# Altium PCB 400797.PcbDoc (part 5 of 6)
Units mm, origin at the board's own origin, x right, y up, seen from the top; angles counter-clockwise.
Board outline 155 x 63.5 mm, 4 copper layers (Top Layer, Mid-Layer 1, Mid-Layer 2, Bottom Layer), stack 1.514 mm thick; 333 components, 292 nets, 1555 pads, 2205 vias.

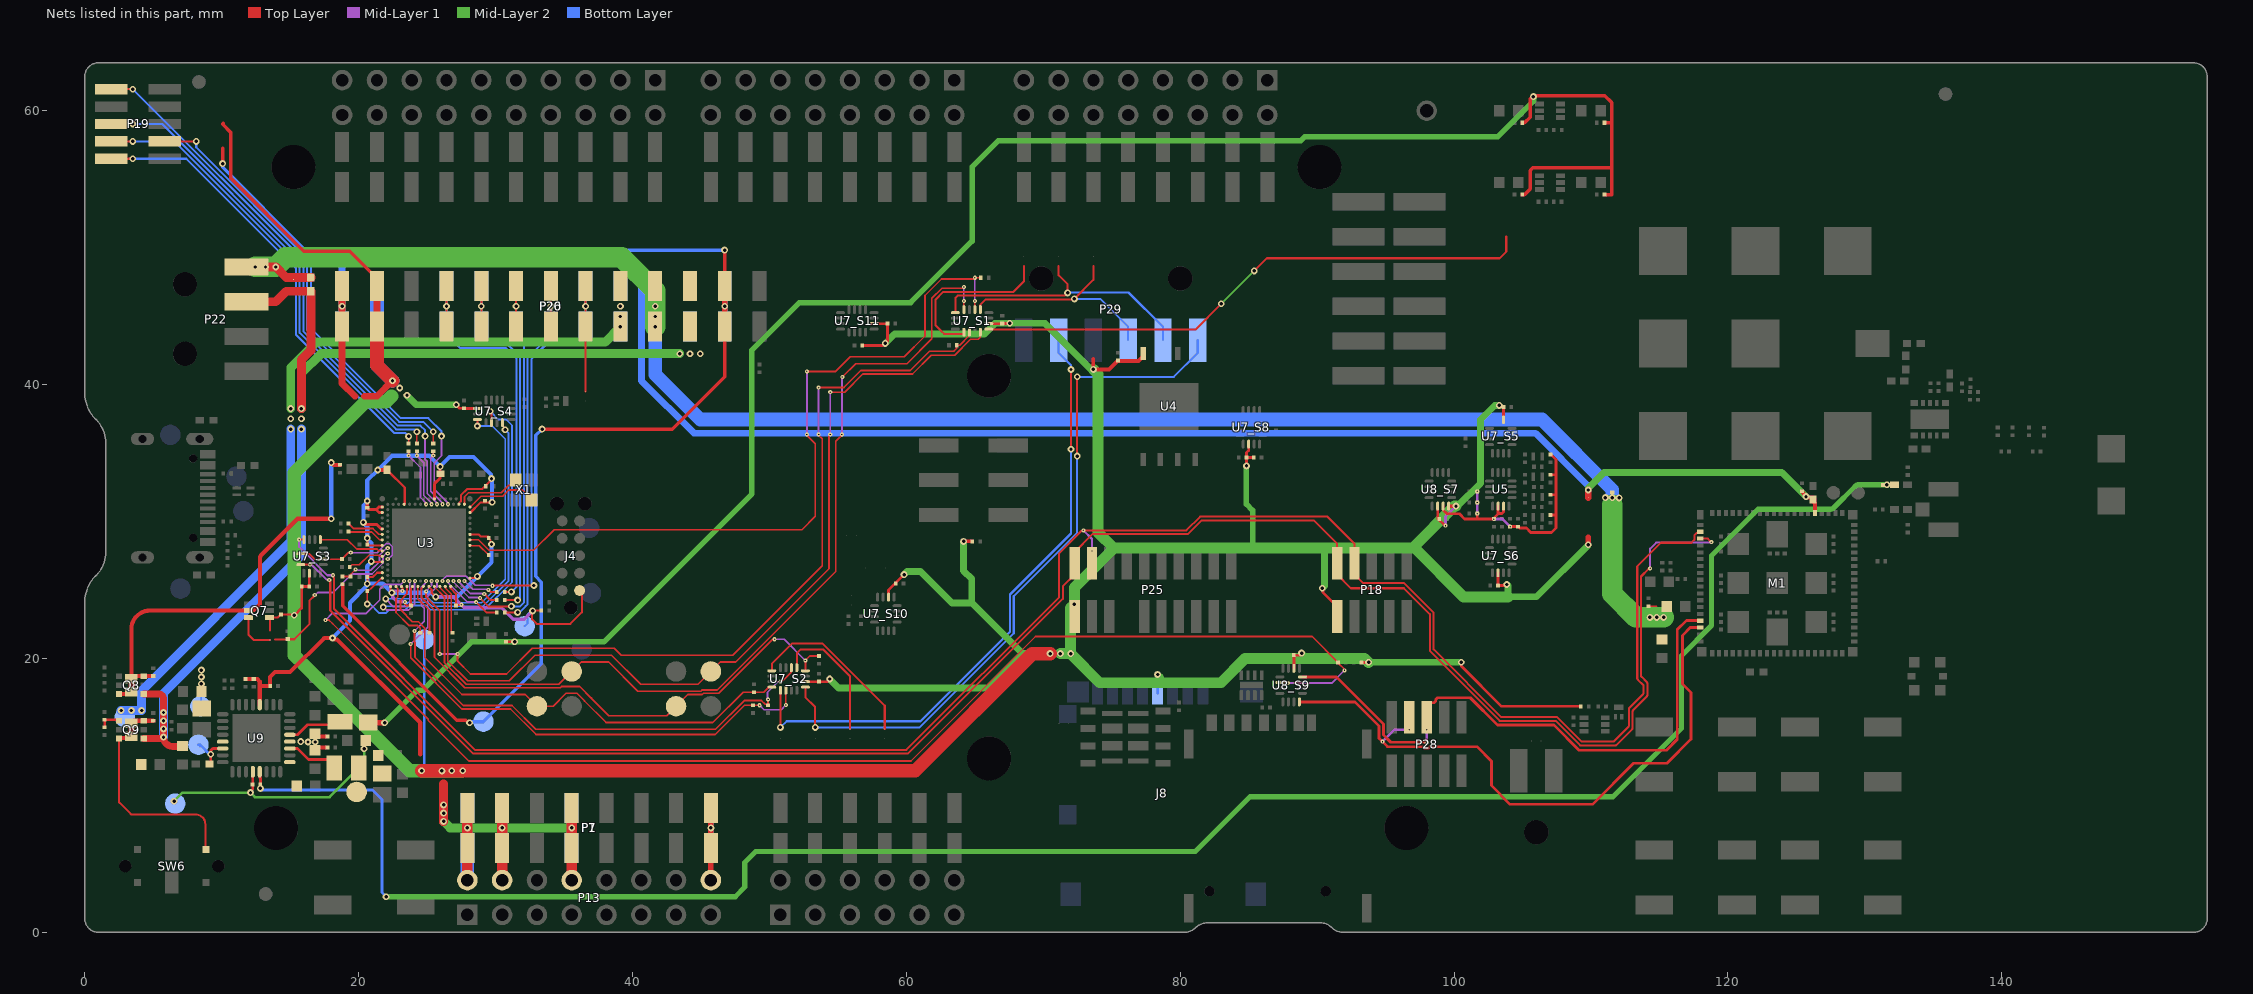
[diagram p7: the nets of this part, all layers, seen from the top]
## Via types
v1: diameter 0.5, hole 0.25, Top Layer to Bottom Layer, tented both sides, 1614 vias
v2: diameter 0.3, hole 0.1, Top Layer to Mid-Layer 1, tented top, 485 vias
v3: diameter 0.3, hole 0.1, Top Layer to Mid-Layer 1, tented both sides, 97 vias
v4: diameter 0.61, hole 0.305, Top Layer to Bottom Layer, tented both sides, 9 vias

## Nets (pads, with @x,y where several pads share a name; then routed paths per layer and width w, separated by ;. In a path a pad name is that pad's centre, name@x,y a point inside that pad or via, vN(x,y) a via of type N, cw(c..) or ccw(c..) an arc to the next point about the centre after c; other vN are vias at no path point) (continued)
SIM_IO: M1.17 P28.4 U8_S9.8 | length 47
  Top Layer w0.203: U8_S9.8@88.7,16.825 92.764,16.825 94.525,15.064 94.525,14.175 v2(94.775,13.925) 95.145,13.555 97.738,13.555 97.844,13.448 98.156,13.448 98.262,13.555 101.659,13.555 102.722,12.492 102.722,10.714 104.089,9.347 110.102,9.347 113.104,12.348 115.543,12.348 117.3,14.106 117.3,17.5 116.672,18.128 116.672,21.672 117.25,22.25 M1.17@117.975,22.25
  Mid-Layer 1 w0.203: v2(94.775,13.925) 95.65,14.8 v2(96.73,14.8)
SIM_RST: M1.16 P28.6 U8_S9.12 | length 43.8
  Top Layer w0.203: U8_S9.12@88.925,18.65 91.403,18.65 94.853,15.2 94.853,14.406 95.377,13.883 97.874,13.883 97.883,13.873 97.925,13.873 97.974,13.825 v2(98,13.825) ; P28.6@98,15.7 98,16.482 98.278,16.76 98.544,16.76 98.663,16.879 98.663,16.994 98.796,17.127 101.18,17.127 103.168,15.138 107.285,15.138 109.125,13.298 115.498,13.298 116.3,14.1 116.3,22.1 116.974,22.774 117.952,22.774 M1.16@117.975,22.75
  Mid-Layer 1 w0.203: v2(98,13.825) v2(98,14.8)
SIM_SELECT: R63.1 U3.AK8 U8_S9.2 | length 96.1
  Top Layer w0.125: v2(17.575,22.8) 17.836,22.8 18.086,22.55 25.088,15.549 25.088,15.466 28.041,12.513 60.337,12.513 69.426,21.602 89.628,21.602 91.552,19.678 91.552,19.648 91.967,19.233 91.967,19.158 v2(92,19.125) ; U8_S9.2@87.275,18.25 87.8,18.25 v2(87.85,18.2)
  Mid-Layer 1 w0.125: v2(17.575,22.8) 18.063,23.288 20.557,23.288 21.537,24.269 21.537,25.046 21.892,25.4 23.066,25.4 v2(23.325,25.659) ; v2(87.85,18.2) 91.075,18.2 v2(92,19.125)
SW1: L7.2 U9.3 | length 3.9
  Top Layer w0.2: U9.3@14.975,13.425 15.538,13.425 16.341,12.622 17.762,12.622 18.227,12.157 L7.2@18.227,11.997
SW2: L8.2 U9.5 | length 4
  Top Layer w0.2: U9.5@14.975,14.425 15.538,14.425 16.28,15.167 18.402,15.167 L8.2@18.625,15.39
SWD0.RESET: P19.10 R30.2 | length 37.6
  Top Layer w0.125: R30.2@25.45,35.694 v1(25.45,36.55)
  Top Layer w0.15: P19.10@1.936,61.571 v1(3.505,61.571)
  Bottom Layer w0.15: v1(3.505,61.571) 16.235,48.84 16.235,44.001 22.961,37.275 24.725,37.275 v1(25.45,36.55)
SWD0.SWDCLK: P19.4 R29.2 | length 34.8
  Top Layer w0.125: R29.2@24.25,35.694 v1(24.25,36.55)
  Top Layer w0.15: P19.4@1.936,57.761 v1(3.505,57.761)
  Bottom Layer w0.15: v1(3.505,57.761) 6.537,57.761 15.685,48.613 15.685,43.773 22.733,36.725 24.075,36.725 v1(24.25,36.55)
SWD0.SWDIO: P19.2 R28.2 | length 33.5
  Top Layer w0.125: R28.2@23.65,35.694 v1(23.65,36.219)
  Top Layer w0.15: P19.2@1.936,56.491 v1(3.505,56.491)
  Bottom Layer w0.15: v1(3.505,56.491) 7.418,56.491 15.41,48.499 15.41,43.659 22.619,36.45 23.419,36.45 v1(23.65,36.219)
SWD0_CLK: R29.1 U3.B18 | length 4.3
  Top Layer w0.125: v2(24.25,34.809) R29.1@24.25,35.124
  Mid-Layer 1 w0.125: v2(24.25,34.809) 24.762,34.297 24.762,31.897 25.063,31.597 25.065,31.597 25.262,31.399 25.262,31.397 25.325,31.334 v2(25.325,31.259)
SWD0_IO: R28.1 U3.B16 | length 4.4
  Top Layer w0.125: v2(23.65,34.809) R28.1@23.65,35.124
  Mid-Layer 1 w0.125: v2(23.65,34.809) 24.512,33.947 24.512,31.749 24.862,31.399 24.862,31.322 v2(24.925,31.259)
SWD0_RESET: R30.1 U3.B22 | length 4.3
  Top Layer w0.125: v2(25.45,34.809) R30.1@25.45,35.124
  Mid-Layer 1 w0.125: v2(25.45,34.809) 25.262,34.622 25.262,32.199 26.063,31.399 26.063,31.347 26.125,31.284 v2(26.125,31.259)
SWD0_SEL: P19.3 U3.B24 | length 38
  Top Layer w0.15: P19.3@5.836,57.761 v1(8.139,57.761)
  Mid-Layer 1 w0.125: v1(26.05,36.234) 26.05,34.809 25.512,34.272 25.512,32.349 26.462,31.399 26.462,31.322 v2(26.525,31.259)
  Bottom Layer w0.15: v1(8.139,57.761) 8.139,57.325 16.51,48.954 16.51,44.115 23.075,37.55 25.086,37.55 26.05,36.586 v1(26.05,36.234)
SWD0_SWO: P19.6 U3.B20 | length 40.8
  Top Layer w0.15: P19.6@1.936,59.031 v1(3.505,59.031)
  Mid-Layer 1 w0.125: v1(24.85,36.234) 24.85,34.563 25.012,34.4 25.012,32.049 25.662,31.399 25.662,31.347 25.725,31.284 v2(25.725,31.259)
  Bottom Layer w0.15: v1(3.505,59.031) 5.656,59.031 15.96,48.726 15.96,43.887 22.847,37 24.5,37 24.85,36.65 v1(24.85,36.234)
SWD1.RESET: P20.7 P26.7 R27.2 | length 28.8
  Top Layer w0.15: R27.2@30.66,23.359 v1(31.609,23.359) ; P20.7@34.036,44.256 v1(34.036,45.721) P20.7@34.036,47.186
  Bottom Layer w0.15: v1(31.609,23.359) 31.759,23.359 32.2,23.8 32.2,23.825 32.338,23.962 32.338,41.972 34.036,43.671 P26.7@34.036,44.256 v1(34.036,45.721) P26.7@34.036,47.186
SWD1.SWDCLK: P20.5 P26.5 R26.2 | length 29.3
  Top Layer w0.15: P20.5@28.956,43.689 P20.5@28.956,44.256 P20.5@28.956,47.186 ; R26.2@30.66,24.259 v1(31.609,24.259)
  Bottom Layer w0.15: P26.5@28.956,47.186 v1(28.956,45.721) 28.956,43.671 29.666,42.961 30.864,42.961 31.788,42.038 31.788,24.438 v1(31.609,24.259)
SWD1.SWDIO: P20.4 P26.4 R25.2 | length 29.9
  Top Layer w0.15: P20.4@26.416,44.349 P20.4@26.416,47.186 ; R25.2@30.66,24.859 v1(31.159,24.859)
  Bottom Layer w0.15: P26.4@26.416,47.186 v1(26.416,45.721) P26.4@26.416,44.256 26.416,43.671 27.401,42.686 30.75,42.686 31.513,41.924 31.513,25.213 v1(31.159,24.859)
SWD1_CLK: R26.1 U3.AK28 | length 3.4
  Top Layer w0.15: v2(29.176,24.71) 29.627,24.259 R26.1@30.09,24.259
  Mid-Layer 1 w0.125: v2(27.325,25.659) 27.325,25.612 27.387,25.549 27.387,25.519 28.16,24.747 29.015,24.747 29.019,24.744 29.143,24.744 v2(29.176,24.71)
SWD1_IO: R25.1 U3.AK30 | length 2.7
  Top Layer w0.15: v2(29.477,25.011) 29.628,24.859 R25.1@30.09,24.859
  Mid-Layer 1 w0.125: v2(27.725,25.659) 28.336,25.048 29.316,25.048 29.319,25.044 29.443,25.044 v2(29.477,25.011)
SWD1_RESET: R27.1 U3.AK24 | length 4.6
  Top Layer w0.15: v2(28.575,24.109) 29.325,23.359 R27.1@30.09,23.359
  Mid-Layer 1 w0.125: v2(26.525,25.659) 26.558,25.626 26.558,25.497 27.937,24.118 28.566,24.118 v2(28.575,24.109)
SWD1_SEL: P20.8 P26.8 SB17.2 U3.AK22 | length 39.5
  Top Layer w0.15: v2(29.777,25.311) 32.786,25.311 v1(32.8,25.325) ; SB17.2@36.576,39.486 SB17.2@36.576,39.498 P20.8@36.576,44.256 v1(36.576,45.721) P20.8@36.576,47.186
  Mid-Layer 1 w0.125: v2(26.125,25.659) 26.125,25.706 26.187,25.769 26.187,25.799 26.385,25.997 27.865,25.997 28.513,25.348 29.616,25.348
  Bottom Layer w0.15: v1(32.8,25.325) 32.613,25.513 32.613,41.859 33.715,42.961 35.866,42.961 36.576,43.671 P26.8@36.576,44.256 v1(36.576,45.721) P26.8@36.576,47.186
SWD1_SWO: P20.6 P26.6 U3.AK26 | length 32.8
  Top Layer w0.15: v2(28.876,24.41) 29.476,23.809 v1@31,23.809 ; P20.6@31.496,43.613 v1(31.496,45.721) P20.6@31.496,47.186
  Mid-Layer 1 w0.125: v2(26.925,25.659) 26.925,25.582 28.06,24.447 28.715,24.447 28.718,24.443 28.842,24.443 v2(28.876,24.41)
  Bottom Layer w0.15: v1(31.159,23.809) 31.795,23.809 32.063,24.076 32.063,43.105 31.496,43.671 P26.6@31.496,44.256 v1(31.496,45.721) P26.6@31.496,47.186
SWD3_CLK: R20.1 U3.R1 | length 2.7
  Top Layer w0.125: R20.1@19.26,29.259 19.26,29.244 19.27,29.234 20.946,29.234 21.521,28.659 U3.R1@21.725,28.659
SWD3_IO: R19.1 U3.N1 | length 2.8
  Top Layer w0.125: R19.1@19.26,29.859 19.26,29.844 19.333,29.772 19.348,29.772 19.635,29.484 21.05,29.484 21.475,29.059 U3.N1@21.725,29.059
SWD3_RESET: R22.1 U3.AA1 | length 2.8
  Top Layer w0.125: R22.1@19.36,26.684 19.514,26.838 20.056,26.838 20.758,27.54 21.444,27.54 21.525,27.459 U3.AA1@21.725,27.459
SWD3_SWO: U3.W1 U7_S3.5 | length 4.9
  Top Layer w0.125: U7_S3.5@17.2,28.675 19.174,28.675 19.852,27.997 21.341,27.997 21.479,27.859 U3.W1@21.725,27.859
SWD_CTRL: R24.2 U3.AB2 U7_S3.2 U7_S3.10 | length 8.5
  Top Layer w0.125: U7_S3.10@15.775,27.65 16.4,27.65 16.8,27.25 U7_S3.2@17.425,27.25 18.765,27.25 19.24,27.725 v2(19.425,27.725)
  Mid-Layer 1 w0.125: v2(19.425,27.725) 21.349,27.725 21.996,28.372 22.254,28.372 22.45,28.176 22.45,27.542 22.167,27.259 v2(22.125,27.259)
SWDCLK: M1.3 P18.4 P25.4 U7_S3.8 | length 144.5
  Top Layer w0.15: v2(15.65,28.675) U7_S3.8@16,28.675 ; v2(18.125,26.075) 18.154,26.046 18.154,25.916 18.2,25.87 18.2,23.616 28.491,13.325 60,13.325 71.15,24.475 71.15,27.678 72.792,29.32 72.898,29.32 v2(72.927,29.348) 80.446,29.348 81.45,30.353 90.752,30.353 92.73,28.375 P18.4@92.73,26.95 92.73,26.13 93.335,25.525 96.317,25.525 98.5,23.342 98.5,20.662 103.447,15.715 107.524,15.715 109.314,13.925 111.588,13.925 ccw(c111.588,14.075) 111.694,13.969 112.721,14.996 ccw(c112.615,15.102) 112.765,15.102 112.765,16.303 cw(c112.915,16.303) 112.809,16.409 113.797,17.397 ccw(c113.69,17.503) 113.84,17.503 113.84,17.972 ccw(c113.69,17.972) 113.797,18.078 113.419,18.456 cw(c113.525,18.562) 113.375,18.562 113.375,26.726 115.099,28.45 117.333,28.45 117.55,28.668 117.55,28.82 117.55,28.983 117.742,29.175 117.9,29.175 M1.3@117.975,29.25
  Mid-Layer 1 w0.15: v2(15.65,28.675) 15.65,28.145 17.72,26.075 v2(18.125,26.075) ; v2(72.927,29.348) 73.555,28.72 v2(73.555,27.85)
SWDIO: M1.4 P18.2 P25.2 U7_S3.12 | length 142.7
  Top Layer w0.15: U7_S3.12@15.775,26.85 v2@16.375,26.85 ; v2(16.45,26.85) v2@16.375,26.85 ; v2@16.45,26.925 v2@16.375,26.85 ; v2(17.85,25.725) 17.85,25.684 17.925,25.609 17.925,23.502 28.377,13.05 60.114,13.05 71.425,24.361 71.425,25.27 72.285,26.13 P25.2@72.285,26.95 72.285,27.77 73.588,29.073 80.559,29.073 81.564,30.078 89.757,30.078 91.46,28.375 P18.2@91.46,26.95 91.46,26.13 92.465,25.125 96.328,25.125 98.225,23.228 98.225,20.548 103.333,15.44 107.41,15.44 109.2,13.65 111.763,13.65 ccw(c111.763,13.8) 111.869,13.694 112.996,14.821 ccw(c112.89,14.927) 113.04,14.927 113.04,14.995 113.04,16.128 cw(c113.19,16.128) 113.084,16.234 114.072,17.222 ccw(c113.965,17.328) 114.115,17.328 114.115,18.172 ccw(c113.965,18.172) 114.072,18.278 ; 114.072,18.278 113.694,18.656 cw(c113.8,18.762) 113.65,18.762 113.65,25.983 114.217,26.55 114.292,26.55 v3(114.321,26.579) ; M1.4@117.975,28.75 118.528,28.75 v3(118.786,28.491)
  Mid-Layer 1 w0.15: v2(16.45,26.85) 16.556,26.85 17.656,25.75 17.825,25.75 v2(17.85,25.725) ; v3(114.321,26.579) 114.321,28.021 114.763,28.463 118.758,28.463 v3(118.786,28.491)
TGT_SCL: U3.AK12 U7_S4.4 | length 26.2
  Top Layer w0.125: U7_S4.4@30.5,37.225 30.5,36.984 30.7,36.784 v1(30.7,36.7)
  Mid-Layer 1 w0.125: v1(21.8,23.75) 22.013,23.538 23.665,23.538 24.075,23.947 24.075,25.609 v2(24.125,25.659)
  Bottom Layer w0.125: v1(21.8,23.75) 21.857,23.807 23.311,23.807 23.617,24.113 25.034,24.113 25.34,23.807 29.078,23.807 30.95,25.679 30.95,36.439 30.7,36.689 v1(30.7,36.7)
TGT_SDA: U3.AK10 U7_S4.16 | length 26.5
  Top Layer w0.125: v1(28.675,36.975) U7_S4.16@28.675,37.45
  Mid-Layer 1 w0.125: v1(21.975,24.35) 22.538,23.788 23.541,23.788 23.725,23.971 v2(23.725,25.659)
  Bottom Layer w0.125: v1(21.975,24.35) 23.501,24.35 23.514,24.363 25.138,24.363 25.444,24.057 28.974,24.057 30.7,25.782 30.7,36.025 29.75,36.975 v1(28.675,36.975)
TGT_TWI_CTRL: R31.1 U3.AJ1 U7_S4.2 | length 28.8
  Top Layer w0.125: v1(20.625,23.975) 20.635,23.985 20.635,24.85 21.063,25.278 21.643,25.859 U3.AJ1@21.725,25.859 ; v1(29.6,38.05) 29.7,37.95 U7_S4.2@29.7,37.225
  Bottom Layer w0.125: v1(20.625,23.975) 20.836,23.975 21.498,23.313 21.981,23.313 22.225,23.557 23.415,23.557 23.721,23.863 24.931,23.863 25.237,23.557 29.182,23.557 31.2,25.575 31.2,37.025 30.775,37.45 30.2,37.45 v1(29.6,38.05)
UART1.CTS: P29.6 SB6.2 U7_S2.13 | length 51.7
  Top Layer w0.15: U7_S2.13@52.625,17.9 52.625,17.17 53.34,16.455 v1(53.34,14.962) ; v1(72.475,34.775) v1(72.475,40.566)
  Bottom Layer w0.15: v1(53.34,14.962) 60.967,14.962 67.842,21.837 67.842,24.554 72.475,29.186 v1(72.475,34.775) ; v1(72.475,40.566) 79.541,40.566 81.28,42.305 P29.6@81.28,43.25
UART1.RTS: P29.2 SB5.2 U7_S2.9 | length 46.2
  Top Layer w0.15: SB5.2@50.8,14.838 SB5.2@50.8,14.85 v1(50.8,14.962) U7_S2.9@50.8,17.675 U7_S2.9@50.8,17.875 ; v1(72.025,35.275) v1(72.025,41.1)
  Bottom Layer w0.15: v1(50.8,14.962) 51.25,15.412 61.028,15.412 67.567,21.951 67.567,24.667 72.025,29.125 v1(72.025,35.275) ; P29.2@71.12,43.25 71.12,42.305 72.025,41.4 v1(72.025,41.1)
UART1.RXD: P29.4 SB3.2 U7_S1.1 | length 16.1
  Top Layer w0.15: U7_S1.1@65.4,45.475 65.4,45.818 65.807,46.225 72.24,46.225 v1(72.268,46.253) 73.66,47.645 SB3.2@73.66,48.65 SB3.2@73.66,48.662
  Bottom Layer w0.15: v1(72.268,46.253) 74.172,46.253 74.221,46.204
  Bottom Layer w0.152: 74.221,46.204 76.2,44.225 P29.4@76.2,43.25
UART1.TXD: P29.5 SB4.2 U7_S1.5 | length 20.6
  Top Layer w0.15: U7_S1.5@63.575,45.25 63.575,46.325 63.75,46.5 71.575,46.5 v1(71.775,46.7) 71.775,47.325 71.12,47.98 SB4.2@71.12,48.662
  Bottom Layer w0.15: v1(71.775,46.7) 71.8,46.725 76.225,46.725 78.74,44.21 P29.5@78.74,43.25
UART2.CTS: SB10.2 U7_S2.5 | length 13
  Top Layer w0.15: U7_S2.5@50.175,19.1 50.175,19.623 51.652,21.1 53.864,21.1 58.42,16.544 SB10.2@58.42,14.85 SB10.2@58.42,14.838
UART2.RTS: SB9.2 U7_S2.1 | length 9.7
  Top Layer w0.15: U7_S2.1@52,19.325 52,20.375 52.288,20.663 53.912,20.663 55.88,18.695 SB9.2@55.88,14.85 SB9.2@55.88,14.838
UART2.RXD: SB7.2 U7_S1.9 | length 12.4
  Top Layer w0.15: U7_S1.9@64.2,43.825 64.2,43.74 64.162,43.702 62.755,43.702 62.55,43.907 62.55,43.914 62.125,44.339 62.125,46.194 62.706,46.775 67.825,46.775 68.58,47.53 SB7.2@68.58,48.65 SB7.2@68.58,48.662
UART2.TXD: SB8.2 U7_S1.13 | length 41.2
  Top Layer w0.15: U7_S1.13@66.025,44.05 66.05,44.025 81.125,44.025 v1(83,45.9) ; v1(85.4,48.3) 86.325,49.225 103.325,49.225 103.81,49.71 SB8.2@103.81,50.801
  Mid-Layer 2 w0.15: v1(83,45.9) v1(85.4,48.3)
USB_DETECT: Q7.3 R74.2 SB29.2 U3.Y2 | length 15.1
  Top Layer w0.15: Q7.3@11.95,23 11.95,21.75 12.35,21.35 SB29.2@13.525,21.35 ; 13.878,21.388 R74.2@14.825,21.388 ; R74.2@14.825,21.415 14.84,21.4 15.3,21.4 16.4,22.5 16.4,24.2 16.796,24.596 v2(16.796,24.637)
  Mid-Layer 1 w0.125: v2(16.796,24.637) 16.837,24.637 17.012,24.812 18.157,24.812 19.507,26.163 20.972,26.163 21.775,26.966 21.775,27.433 22.001,27.659 v2(22.125,27.659)
VBUS: Q7.2 Q8.3 Q8.6 R21.1 R78.2 | length 32.2
  Top Layer w0.3: Q8.3@2.495,17.4 3.225,17.4 ccw(c3.225,17.575) Q8.3@3.4,17.575 ; Q8.6@4.305,18.7 Q8.6@4.305,18.715 ; R78.2@5,18.715 Q8.6@4.305,18.715 ; v1(18,30.2) 15.542,30.2 12.888,27.545 ccw(c13.1,27.333) 12.8,27.333 12.8,23.961 12.364,23.525 11.975,23.525 Q7.2@11.95,23.5 4.767,23.5 ccw(c4.767,22.133) 3.4,22.133 Q8.6@3.4,18.525 3.59,18.715 Q8.6@4.305,18.715 ; v1(18,34.3) 18.165,34.135 R21.1@18.625,34.135
  Top Layer w0.5: Q8.3@3.4,17.575 Q8.6@3.4,18.525
  Bottom Layer w0.3: v1(18,30.2) v1(18,34.3)
VBUSOUT: C64.2 TP25.1 U9.22 | length 3.3
  Top Layer w0.2: C64.2@9.1,12.3 ccw(c9.1,12.4) 9.2,12.4 v1(9.2,13) 9.2,13.2 cw(c9.425,13.2) 9.425,13.425 U9.22@10.075,13.425
  Bottom Layer w0.15: TP25.1@8.3,13.7 TP25.1@8.425,13.575
  Bottom Layer w0.2: TP25.1@8.3,13.7 8.419,13.7 9.119,13 v1(9.2,13)
VCOM0_CTRL: R13.1 U3.R31 U7_S1.2 | length 57
  Top Layer w0.125: U3.R31@28.125,28.659 28.754,28.659 29.516,27.896 32.771,27.896 34.275,29.4 52.375,29.4 53.35,30.375 53.35,35.685 52.737,36.298 v2(52.737,36.35) ; v2(52.737,40.963) 54.841,40.963 55.904,42.025 59.839,42.025 61.362,43.548 61.362,46.509 62.566,47.713 64.913,47.713 v2(65,47.8) R13.1@65.44,47.8 ; U7_S1.2@65,45.475 v2(65,46.1)
  Mid-Layer 1 w0.125: v2(52.737,36.35) v2(52.737,40.963) ; v2(65,46.1) v2(65,47.8)
VCOM0_CTS: R86.1 TP5.1 U3.AL9 U7_S2.8 | length 35.9
  Top Layer w0.125: U3.AL9@23.525,25.259 23.525,24.717 23.062,24.254 23.062,23.548 23.923,22.688 24.366,22.688 24.838,22.216 24.838,20.072 27.547,17.363 32.168,17.363 32.822,16.708 32.822,16.312 TP5.1@33.02,16.51 34.201,16.51 35.139,17.448 35.948,17.448 36.498,16.898 36.498,16.895 38.07,15.323 45.858,15.323 48.076,17.54 R86.1@48.875,17.54 49.59,17.54 49.95,17.9 U7_S2.8@50.175,17.9
VCOM0_HWFC: R17.1 U3.AK16 U7_S2.2 | length 38.7
  Top Layer w0.125: v2(24.075,22.004) 24.075,21.217 24.113,21.179 24.113,20.09 27.64,16.563 31.198,16.563 32.938,14.823 46.065,14.823 48.165,16.923 49.425,16.923 49.69,16.658 49.828,16.658 R17.1@49.9,16.585 v2(49.9,17) ; v2(50.8,18.3) 50.9,18.3 51.6,19 U7_S2.2@51.6,19.325
  Mid-Layer 1 w0.125: v2(24.075,22.004) 24.788,22.716 24.788,23.658 24.587,23.858 24.587,25.237 24.853,25.503 24.853,25.54 24.925,25.612 v2(24.925,25.659) ; v2(49.9,17) 49.862,17.038 49.862,17.54 50.623,18.3 v2(50.8,18.3)
VCOM0_RTS: R15.1 U3.AL5 | length 4.6
  Top Layer w0.125: U3.AL5@22.725,25.259 22.725,25.235 22.862,25.097 22.862,24.488 22.725,24.35 22.725,23.351 23.663,22.413 24.288,22.413 24.5,22.2 R15.1@24.5,21.869
VCOM0_RXD: TP4.1 U3.AL19 U7_S1.4 | length 69.7
  Top Layer w0.125: U3.AL19@25.525,25.217 25.542,25.217 26.262,24.497 26.262,20.465 26.263,20.185 26.262,19.708 27.858,18.113 34.622,18.113 TP4.1@35.56,19.05 36.248,19.738 38.262,19.738 40.388,17.613 44.991,17.613 45.076,17.698 46.194,17.698 54.85,26.354 54.85,35.86 55.288,36.298 v2(55.288,36.35) ; v2(55.325,40.55) 56.3,41.525 60.046,41.525 61.862,43.341 61.862,46.302 62.598,47.038 64.088,47.038 v2@64.175,47.125 ; U7_S1.4@64.2,45.475 v2(64.2,46.1)
  Top Layer w0.15: U3.AL19@25.525,25.217 U3.AL19@25.525,25.259
  Mid-Layer 1 w0.125: v2(55.288,36.35) 55.306,36.369 55.306,40.531 v2(55.325,40.55) ; v2@64.175,47.125 64.2,47.1 v2(64.2,46.1)
  other v2: 64.2,47.125
VCOM0_TXD: R11.1 U3.U31 | length 1.7
  Top Layer w0.125: U3.U31@28.125,28.259 28.144,28.24 28.819,28.24 R11.1@29.5,27.559
VCOM1_CTRL: R14.2 U3.AK18 U7_S1.10 | length 64.5
  Top Layer w0.125: v2@24.925,24.925 v2(24.925,24.9) 24.925,24.475 25.925,23.475 v2(25.925,20.325) ; v2(27.225,20.325) 27.225,19.806 28.169,18.863 30.8,18.863 32.675,20.738 38.677,20.738 39.177,20.238 47.32,20.238 53.85,26.768 53.85,36.035 53.588,36.298 v2(53.588,36.35) ; v2@53.588,39.75 53.625,39.788 55.438,39.788 56.675,41.025 60.275,41.025 61.688,42.438 63.459,42.438 63.661,42.639 63.661,42.851 R14.2@63.685,42.875 63.886,42.875 64.6,43.589 U7_S1.10@64.6,43.825
  Mid-Layer 1 w0.125: v2@24.925,24.925 25.325,25.325 v2(25.325,25.659) ; v2(25.925,20.325) v2(27.225,20.325) ; v2(53.588,36.35) v2(53.588,39.775)
VCOM1_CTS: R85.1 TP9.1 U3.AL15 U7_S2.16 | length 39.4
  Top Layer w0.125: U3.AL15@24.725,25.259 24.725,25.235 24.575,25.085 24.575,24.471 25.538,23.509 25.538,20.079 27.754,17.863 34.726,17.863 34.811,17.948 36.152,17.948 36.155,17.948 36.998,17.105 36.998,17.102 38.277,15.823 42.492,15.823 TP9.1@43.18,16.51 44.032,17.363 45.095,17.363 45.18,17.448 46.298,17.448 50.25,21.4 v2(50.375,21.4) ; v2(52.625,19.85) 52.96,20.185 R85.1@53.625,20.185
  Top Layer w0.15: U7_S2.16@52.625,19.1 v2(52.625,19.85)
  Mid-Layer 1 w0.125: v2(50.375,21.4) 51.075,21.4 v2(52.625,19.85)
VCOM1_HWFC: R18.2 U3.AK20 U7_S2.10 | length 38.4
  Top Layer w0.125: v2(23.8,21.05) 23.8,20.049 27.537,16.313 31.095,16.313 32.957,14.45 46.046,14.45 48.181,16.585 v2(49.285,16.585) ; v2(51.2,16.6) U7_S2.10@51.2,17.675
  Mid-Layer 1 w0.125: v2(23.8,21.05) 25.038,22.288 25.038,24.535 25.725,25.223 v2(25.725,25.659) ; v2(49.285,16.585) 49.608,16.263 50.862,16.263 v2(51.2,16.6)
VCOM1_RTS: R16.1 U3.AL13 | length 3.7
  Top Layer w0.125: U3.AL13@24.325,25.259 24.325,24.368 25.175,23.518 R16.1@25.175,21.869
VCOM1_RXD: TP8.1 U3.AL21 U7_S1.12 | length 65.2
  Top Layer w0.125: U3.AL21@25.925,25.235 25.925,25.188 25.976,25.138 ; 25.976,25.137 26.512,24.6 26.512,20.568 26.513,20.082 26.512,19.811 27.961,18.363 31.007,18.363 32.882,20.238 38.47,20.238 40.595,18.113 44.782,18.113 TP8.1@45.72,19.05 46.408,19.738 47.527,19.738 54.35,26.561 54.35,36.263 v2(54.438,36.35) ; v2(54.438,39.45) 55.5,39.45 56.825,40.775 60.45,40.775 61.825,42.15 63.525,42.15 64.687,43.313 65.257,43.313 65.4,43.455 U7_S1.12@65.4,43.825
  Mid-Layer 1 w0.125: v2(54.438,36.35) v2(54.438,39.45)
VCOM1_TXD: R12.1 U3.AL23 | length 3.6
  Top Layer w0.125: U3.AL23@26.325,25.259 26.344,25.24 26.344,25.122 26.762,24.704 26.762,21.932 R12.1@26.825,21.869
VDD: C42.2 C52_S1.1 C52_S2.1 C52_S3.1 C52_S4.1 C52_S5.1 C52_S6.1 C52_S8.1 C52_S10.1 C52_S11.1 C53_S7.1 C53_S9.1 J8.4 P18.1 P20.2 P25.1 P26.2 Q7.4 R8.1 R23.2 R35.2 R62.1 R66.1 R69.2 R75.1 SB1.1 SB16.2 SB20.1 SB29.1 SB30.2 SB31.1 SB32.1 SB33.2 TP23.1 U4.8 U7_S1.14 U7_S2.14 U7_S3.14 U7_S4.14 U7_S5.14 U7_S6.14 U7_S8.14 U7_S10.14 U7_S11.14 U8_S7.14 U8_S7.16 U8_S9.14 | length 353.5
  Top Layer w0.15: SB29.1@13.525,22.05 13.525,22.975 Q7.4@13.5,23 14.11,23 R75.1@14.325,23.215 15.235,23.215 v1(15.3,23.15)
  Top Layer w0.2: v1(15.3,23.15) 15.835,23.685 C52_S3.1@15.835,25.25 16.335,25.25 16.4,25.315 U7_S3.14@16.4,26.225 ; v1(27.125,38.525) 27.385,38.265 C52_S4.1@27.7,38.265 27.715,38.25 U7_S4.14@28.675,38.25 ; U7_S2.14@52.625,18.3 54.2,18.3 v1(54.4,18.5) ; R66.1@56.785,42.85 58.3,42.85 v1(58.458,43.008) 58.615,43.165 C52_S11.1@58.615,44.45 U7_S11.14@57.643,44.45 ; U7_S10.14@58.7,24.475 58.7,24.993 v1(59.832,26.125) ; U7_S1.14@66.025,44.45 66.985,44.45 C52_S1.1@67,44.465 67.54,44.465 v1(67.55,44.475) ; v1(84.838,34.062) C52_S8.1@84.838,34.671 ; U7_S8.14@85,35.65 85,35.193 84.838,35.031 C52_S8.1@84.838,34.671 ; R35.2@85.368,34.671 C52_S8.1@84.838,34.671 ; U8_S9.14@88.3,19.275 88.3,20.235 v1@88.86,20.235 ; v1(90.375,25.125) 90.432,25.068 90.432,24.818 91.46,23.79 P18.1@91.46,23.05 ; R62.1@93.235,19.7 v1@93.752,19.7 ; U8_S7.14@98.8,31.125 98.8,30.225 99.325,29.7 v2(99.375,29.7) v2@99.4,29.7 ; v1(100.525,19.718) 100.525,19.45 103.475,16.5 R8.1@109.255,16.5 ; U7_S6.14@103.21,26.259 103.208,26.257 C52_S6.1@103.208,25.334 103.217,25.325 103.775,25.325 v1(103.85,25.4)
  Top Layer w0.22: v1(103.3,38.475) 103.376,38.475 103.452,38.399 103.588,38.399 103.61,38.377 U7_S5.14@103.61,37.434
  Top Layer w0.25: v1(73.66,41.11) SB20.1@73.66,41.855 73.66,41.893
  Top Layer w0.254: SB16.2@10.1,59.095 10.062,59.057 10.062,59 10.675,58.387 10.675,55.075 16,49.75 19.35,49.75 21.336,47.764 P20.2@21.336,46.949 ; v1(64.176,28.55) R69.2@64.815,28.55 ; U8_S7.16@99.6,31.125 v1(100.137,31.125)
  Top Layer w0.3: v1(73.66,41.11) 74.795,41.11 75.41,41.725 76.95,41.725 77.282,42.057 U4.8@77.282,42.27
  Top Layer w0.4: v1(109.8,28.3) SB1.1@109.8,28.85
  Top Layer w0.5: 20.404,39.148 21.337,39.148 v1(22.47,40.28)
  Top Layer w0.508: P20.2@21.336,44.256 P20.2@21.336,46.949
  Top Layer w1: P20.2@21.336,44.256 21.336,41.414 v1(22.47,40.28) ; v1@24.6,11.8 25.3,11.8 26.078,11.8 60.65,11.8 69.2,20.35 v1(70.5,20.35)
  Mid-Layer 1 w0.2: v2(99.375,29.7) 99.375,30.363 v1(100.137,31.125)
  Mid-Layer 2 w0.4: v1(84.838,34.062) 84.838,31.265 85.282,30.821 85.282,28.05
  Mid-Layer 2 w0.5: v1(23.53,39.22) 24.225,38.525 v1(27.125,38.525) ; v1(54.4,18.5) 55.05,17.85 65.975,17.85 68.475,20.35 ; v1(58.458,43.008) 59.15,43.7 65.7,43.7 66.475,44.475 v1(67.55,44.475) 70.125,44.475 73.49,41.11 v1(73.66,41.11) ; v1(59.832,26.125) 60.057,26.35 61.025,26.35 63.325,24.05 64.775,24.05 ; v1(64.176,28.55) 64.176,26.399 64.775,25.8 64.775,24.05 ; v1(70.5,20.35) 68.475,20.35 ; v1(78.35,18.825) 78.58,18.595 78.58,18.225 ; v1(88.86,20.385) 89.13,20.115 89.13,20 ; v1(90.375,25.125) 90.53,25.28 90.53,28.05 ; v1(93.752,19.718) v1(100.525,19.718) ; v1(100.137,31.125) 100.259,31.125 101.925,32.791 101.925,37.431 102.969,38.475 v1(103.3,38.475) ; v1(103.85,25.4) 103.93,25.32 103.93,24.5 106,24.5 v1(109.8,28.3) ; 64.775,24.05 68.475,20.35
  Mid-Layer 2 w0.8: v1(71.25,20.35) 71.975,20.35 74.1,18.225 78.58,18.225 82.968,18.225 84.743,20 89.13,20 93.47,20 v1(93.752,19.718) ; v1(72,20.35) 72,23.675 v1(72.275,23.95) 72.275,25.17 75.155,28.05 ; v1(73.66,41.11) 74,40.77 74,29.205 75.155,28.05 ; v1(100.137,31.125) 100.025,31.125 96.95,28.05 ; 103.93,24.5 100.693,24.5 97.143,28.05 96.95,28.05 ; 75.155,28.05 85.282,28.05 90.53,28.05 96.95,28.05
  Mid-Layer 2 w1: 22.4,39.15 22,38.75 20.5,38.75 15.3,33.55 15.3,20.228 23.728,11.8 v1(26.8,11.8) v1(27.6,11.8)
  Bottom Layer w0.2: v1(24.595,11.799) 24.595,11.865 24.795,12.066 TP23.1@24.795,21.38 ; J8.4@78.35,17.47 v1(78.35,18.825)
  Bottom Layer w1: P26.2@21.336,47.186 P26.2@21.336,44.256 21.336,41.414 v1(22.47,40.28)
  other v1: 26.078,11.785 23,39.75
VDD_1V8: C60.2 C69.2 FB5.1 L7.1 TP21.1 U9.1
VDD_3V0: C72.2 FB6.2 R33.2 R39.2 R40.2 R41.2 R42.2 R87.1 TP27.1 U9.28 | length 156.1
  Top Layer w0.2: v1(12.1,10.2) 12.1,10.281 12.257,10.438 12.257,10.75 12.252,10.755 R87.1@12.252,10.8 12.264,10.812 12.264,11.714 U9.28@12.275,11.725 ; R33.2@30.75,21.215 v1(31.39,21.215)
  Top Layer w0.25: R41.2@104.983,53.868 105.143,53.868 105.556,54.281 105.556,55.632 105.747,55.823 111.496,55.823 ; R39.2@104.983,59.118 105.143,59.118 105.556,59.531 105.556,60.882 ; v1(105.79,61.033) 105.856,61.1 111,61.1 111.499,60.601 111.499,53.868 R42.2@110.983,53.868 ; R40.2@110.983,59.118 111.499,59.118
  Top Layer w0.4: FB6.2@20.7,15.325 20.725,15.3 v1(21.9,15.3)
  Mid-Layer 2 w0.2: v1(6.525,9.575) 7.15,10.2 v1(12.1,10.2) 12.429,9.871 17.871,9.871 20.4,12.4 v1(20.4,13.4)
  Mid-Layer 2 w0.4: v1(21.9,15.3) 24.293,17.693 24.707,17.693 28.228,21.215 v1(31.39,21.215) 37.915,21.215 48.714,32.014 48.714,42.514 52.189,45.989 60.311,45.989 64.8,50.479 64.8,55.9 66.7,57.8 88.8,57.8 89.1,58.1 103.2,58.1 105.8,60.7 105.8,61 105.79,61.01 v1(105.79,61.033)
VDD_5V: C54.2 C58.2 P20.11 P22.2 P26.11 Q8.4 Q9.4 R82.2 SB34.2 SB35.1 U9.21 | length 79
  Top Layer w0.5: Q9.4@4.305,14.15 5.65,14.15 v1(5.75,14.25) ; Q8.4@4.305,17.4 5.4,17.4 cw(c5.4,17.05) 5.75,17.05 v1(5.75,16.05) v1(5.75,15.45) v1(5.75,14.85) v1(5.75,14.25) ; C54.2@7.127,13.597 cw(c7.105,13.597) 7.105,13.575 6.425,13.575 cw(c6.425,14.25) v1(5.75,14.25)
  Top Layer w0.65: P22.2@11.811,46.049 13.946,46.049 14.716,46.819 R82.2@16.51,46.819 16.51,42.491 15.819,41.8 v1(15.819,38.25)
  Mid-Layer 2 w0.65: v1(15.819,38.25) 15.819,40.819 17.256,42.256 v1(43.446,42.256)
  Bottom Layer w0.65: v1(5.75,14.25) v1(5.75,14.85) v1(5.75,15.45) v1(5.75,16.05) 5.75,17.45 15.819,27.519 v1(15.819,36.75)
  other v1: 15.819,37.5 44.196,42.256 44.946,42.256
VDD_GNSS: C11.2 L3.1 R87.2 U9.29 | length 146.8
  Top Layer w0.2: U9.29@12.775,11.725 12.775,11.423 12.794,11.404 12.794,11.283 12.827,11.25 12.827,10.85 12.822,10.846 12.828,10.839 v1(12.828,10.504)
  Mid-Layer 2 w0.381: v1@22.032,2.6 47.5,2.6 48.2,3.3 48.2,5.1 49,5.9 81.1,5.9 85.1,9.9 111.6,9.9 116.6,14.9 116.6,20.2 118.8,22.4 118.8,27.5 122.2,30.9 127.467,30.9 ccw(c127.467,31.281) 127.736,31.011 129.299,32.574 cw(c129.568,32.304) 129.568,32.685 v1(131.606,32.685)
  Bottom Layer w0.2: v1(12.828,10.504) 12.831,10.5 ccw(c13.004,10.6) 13.004,10.4 21,10.4 21.7,9.7 21.7,2.9 v1(22,2.6)
VDD_GPIO: C4.1 C5.1 M1.65 P20.1 P26.1 SB2.1 SB31.2 | length 136.1
  Top Layer w0.305: C4.1@125.4,32.185 125.602,31.983 125.602,31.97 125.7,31.872 v1(125.7,31.819) ; v1@125.691,31.8 125.753,31.8 125.805,31.748 126.202,31.748 126.3,31.65 126.3,31.4 126.35,31.35 M1.65@126.35,30.625
  Top Layer w0.5: 18.796,41.891 18.796,40.08 SB31.2@19.728,39.148 ; SB2.1@109.8,31.75 v1(109.8,32.3)
  Top Layer w0.508: 18.796,41.891 P20.1@18.796,44.256 P20.1@18.796,47.186
  Mid-Layer 2 w0.5: v1(109.8,32.3) 109.8,32.45 110.937,33.587 123.933,33.587 v1(125.7,31.819)
  Bottom Layer w0.5: P26.1@18.796,47.186 18.796,48.821 19.3,49.325 39.575,49.325 40.65,48.25 40.65,40.275 44.479,36.446 105.929,36.446 109.8,32.575 v1(109.8,32.3)
  Bottom Layer w0.508: P26.1@18.796,44.256 P26.1@18.796,47.186
  other v1: 18.796,45.721
VDD_IMCU: C24.2 C25.2 C26.1 C27.2 C28.1 C31.2 C32.2 C33.2 C34.1 C35.2 C62.1 J4.1 R34.2 R83.2 R84.2 SB32.2 TP12.1 U3.A19 U3.AC1 U3.AG1 U3.AJ31 U3.AL3 U3.AL7 U3.AL11 U3.AL17 U3.AL25 U3.B8 U3.B28 U3.C1 U3.E1 U3.E31 U3.L1 U3.N31 U3.U1 U9.12 | length 105.2
  Top Layer w0.15: v1@20.635,25.459 C26.1@20.635,25.959 ; C25.2@20.635,28.259 U3.U1@21.725,28.259 ; C25.2@20.635,28.334 v1@20.635,28.784 ; C26.1@20.65,25.959 21.05,25.959 21.35,26.259 U3.AG1@21.725,26.259 ; v1@20.925,27.059 U3.AC1@21.725,27.059 ; v1@22.325,24.794 U3.AL3@22.325,25.259 ; v2(23.2,24.923) U3.AL7@23.2,25.184 ; v2(23.375,24.125) 23.375,24 23.506,23.869 C27.2@23.827,23.869 23.838,23.88 23.838,25.151 23.925,25.239 U3.AL11@23.925,25.259 ; U3.AL17@25.125,25.217 25.34,25.002 25.34,24.779 v1(25.625,24.494) ; U3.AL25@26.725,25.259 26.725,25.113 27.1,24.738 C31.2@27.1,23.869 27.125,23.894 27.475,23.894 v2(27.5,23.919) ; U3.B28@27.325,31.259 27.325,31.334 27.462,31.472 27.462,31.916 27.918,32.372 29.013,32.372 29.141,32.5 29.23,32.5 29.261,32.531 29.261,32.62 29.7,33.059 v1(29.7,33.134) ; U3.AJ31@28.125,25.859 28.443,25.859 ; U3.N31@28.125,29.059 28.75,29.059 28.9,28.909 C32.2@29.49,28.909 ; U3.E31@28.125,30.659 28.167,30.659 28.892,31.384 v1@29.75,31.384 ; C32.2@29.428,28.847 29.634,28.64 29.634,28.4 v1(29.7,28.334) ; R34.2@33.34,23.5 32.725,23.5 v1(32.7,23.475) 32.675,23.45 32.675,22.85 33,22.525 35.467,22.525 36.3,23.359 36.3,24.795 J4.1@36.135,24.96
  Top Layer w0.187: C35.2@22.175,33.839 22.175,33.667 23.368,32.474 23.368,31.302 U3.B8@23.325,31.259
  Top Layer w0.2: v1(20.35,29.934) 20.5,29.784 21.323,29.784 21.648,29.459 U3.L1@21.725,29.459 ; C24.2@20.625,30.994 20.644,30.959 ccw(c20.809,31.072) 20.809,30.872 21.287,30.872 ; U3.E1@21.725,30.659 21.72,30.664 21.495,30.664 21.287,30.872 ; U3.C1@21.725,31.059 21.475,31.059 21.287,30.872
  Top Layer w0.225: U3.A19@25.525,31.659 25.525,32.754 25.95,33.179 v1(25.95,34.009)
  Top Layer w0.25: C24.2@20.625,30.994 20.619,31 20.619,31.492 v1(20.625,31.497)
  Top Layer w0.3: R84.2@11.737,18.502 11.739,18.5 12.599,18.5 12.775,18.324 12.775,18 ; U9.12@12.775,16.625 12.775,18 ; v1(18.091,21.491) 18.145,21.491 18.245,21.391 18.415,21.391 24.5,15.305 24.5,13 ; v1@18.109,21.491 17.491,21.491 15,19 13.9,19 13.54,18.64 C62.1@13.54,17.975 12.8,17.975 12.775,18 ; v1(21.4,33.759) C35.2@22.025,33.759
  Mid-Layer 1 w0.25: v1(22.423,24.794) 22.475,24.742 22.475,24.467 22.817,24.125 v2(23.375,24.125) ; v1@22.527,24.923 v2(23.2,24.923) ; v1(25.625,24.494) 26.925,24.494 v2(27.5,23.919) 27.71,23.709 30.441,23.709 31.291,22.859 32.084,22.859 v1(32.7,23.475)
  Bottom Layer w0.15: TP12.1@32.129,22.353 32.343,22.567 32.343,23.218 32.533,23.408 32.633,23.408 v1(32.7,23.475)
  Bottom Layer w0.3: v1(18.091,21.491) 19.375,22.775 19.375,24.067 20.587,25.279 20.587,25.367 v1@20.625,25.367 ; v1(29.7,28.334) 29.7,27.022 v1(28.675,25.997) 27.173,24.494 v1(25.625,24.494) 25.571,24.494 25.271,24.794 v1(22.423,24.794) 21.758,25.459 v1(20.625,25.459) 20.625,26.734 20.925,27.034 v1(20.925,27.088) 20.925,28.43 20.625,28.73 v1(20.625,28.784) 20.625,29.605 20.35,29.88 v1(20.35,29.934) 20.35,31.168 20.625,31.443 v1(20.625,31.497) 20.625,32.984 v1(21.4,33.759) 22.441,34.8 25.159,34.8 v1(25.95,34.009) 26.641,34.7 28.4,34.7 29.662,33.438 29.662,33.172 v1(29.7,33.134) 29.725,33.109 29.725,31.434 v1(29.75,31.409)
VDD_nRF: C1.1 C2.1 C3.1 FB1.1 P20.10 P22.1 P26.10 R82.1 SB34.1 | length 127.1
  Top Layer w0.125: C1.1@114.19,23.815 114.8,23.815
  Top Layer w0.65: P22.1@11.811,48.589 v1(12.446,48.589) v1(13.196,48.589) v1(13.946,48.589) 14.716,47.819 R82.1@16.51,47.819
  Mid-Layer 2 w1.5: v1(12.446,48.589) v1(13.196,48.589) v1(13.946,48.589) 14.657,49.3 39.2,49.3 41.656,46.844 v1(41.656,45.721) v1(41.656,44.971) v1(41.656,44.221) ; 111.55,31.226 111.55,24.725 113.28,22.995 v1(114.298,22.995) ; v1@114.298,22.992 115.301,22.992 v1(115.305,22.996)
  Bottom Layer w1: P26.10@41.656,44.256 v1(41.656,44.221) 41.656,40.742 44.948,37.45 106.425,37.45 111.55,32.325 v1@111.55,31.85
  other v1: 114.8,23 112.053,31.729 111.048,31.745 111.55,31.75
VIN: P1.8 P7.8 P13.16 | length 8.2
  Top Layer w0.381: P13.16@45.72,3.811 P1.8@45.72,6.156 v1(45.72,7.621) P1.8@45.72,9.086
  Bottom Layer w0.381: P7.8@45.72,6.156 v1(45.72,7.621) P7.8@45.72,9.086
VIN:5V: P20.9 P26.9 Q9.1 R79.2 R80.1 TP22.1 | length 56.5
  Top Layer w0.2: R79.2@1.45,14.985 R80.1@1.45,15.515 2.43,15.515 Q9.1@2.495,15.45
  Mid-Layer 2 w0.65: v1(15.044,38.25) 15.044,41.244 16.9,43.1 37.995,43.1 v1(39.116,44.221)
  Bottom Layer w0.65: v1(2.65,16.2) v1(3.4,16.2) v1(4.15,16.2) 4.15,17.65 15.044,28.544 v1(15.044,36.75)
  other v1: 15.044,37.5 39.116,44.971 39.116,45.721
VIN_5V: Q9.3 Q9.6 R81.1 SW6.6 | length 17.3
  Top Layer w0.15: Q9.3@2.495,14.15 2.495,9.567 ccw(c2.645,9.567) 2.539,9.461 3.356,8.644 ccw(c3.462,8.75) 3.462,8.6 8.1,8.6 cw(c8.1,7.9) 8.8,7.9 SW6.6@8.8,6.085
  Top Layer w0.3: Q9.3@2.495,14.15 2.547,14.202 Q9.3@3.182,14.202 ; Q9.3@3.1,14.12 Q9.3@3.182,14.202 ; Q9.3@3.4,14.325 3.305,14.325 Q9.3@3.182,14.202 ; Q9.6@3.4,15.275 3.575,15.45 Q9.6@4.305,15.45 R81.1@5,15.45 ; SW6.6@8.8,6.085 ccw(c8.85,6.085) SW6.6@8.85,6.035
  Top Layer w0.5: Q9.3@3.4,14.325 Q9.6@3.4,15.275
VIO: P1.1 P1.2 P1.4 P7.1 P7.2 P7.4 P13.2 P13.4 P13.8 SB30.1 | length 39.4
  Top Layer w0.65: SB30.1@26.195,10.849 26.2,10.849 v1(26.2,9.3) v1(26.2,8.7) v1(26.2,8.1)
  Top Layer w0.75: P13.2@27.94,3.811 P1.1@27.94,9.086 ; P13.4@30.48,3.811 P1.2@30.48,9.086 ; P13.8@35.56,3.811 v1(35.56,7.621) P1.4@35.56,9.086
  Mid-Layer 2 w0.65: v1(26.2,9.3) v1(26.2,8.7) v1(26.2,8.1) 26.679,7.621 v1(27.94,7.621) v1(30.48,7.621) v1(35.56,7.621)
  Bottom Layer w0.762: P7.1@27.94,6.156 P7.1@27.94,9.086 ; P7.2@30.48,6.156 P7.2@30.48,9.086 ; P7.4@35.56,6.156 P7.4@35.56,9.086
  Bottom Layer w1: P13.2@27.94,3.811 27.94,5.061
VIO_REF: P20.12 P26.12 R64.1 SB15.2 TP16.1 | length 107.1
  Top Layer w0.25: v1(10.062,56.138) 10.062,57.25 ; R64.1@18.825,25.415 18.825,23.839 27.164,15.5 27.832,15.5 28.032,15.3 v1(28.1,15.3) ; v1(33.4,36.75) 42.9,36.75 46.736,40.586 P20.12@46.736,44.256 ; v1@46.7,49.825 46.736,49.789 P20.12@46.736,46.991
  Top Layer w0.381: P20.12@46.736,44.256 v1(46.736,45.721) P20.12@46.736,46.991
  Bottom Layer w0.25: v1(10.062,56.138) 10.062,55.861 16.099,49.825 v1@46.7,49.825 ; v1(28.1,15.3) 28.186,15.386 TP16.1@29.108,15.386 33.35,19.627 33.35,25.575 32.938,25.988 32.938,36.288 v1(33.4,36.75) ; P26.12@46.736,47.186 P26.12@46.736,47.764
  Bottom Layer w0.381: P26.12@46.736,44.256 v1(46.736,45.721) P26.12@46.736,47.186
  other v1: 46.725,49.825
VIO_REF_SENSE: R64.2 R65.2 U3.V2 | length 4.6
  Top Layer w0.125: R64.2@18.825,25.985 R65.2@19.4,25.985 19.4,26.125 v2(19.775,26.5)
  Mid-Layer 1 w0.125: v2(19.775,26.5) 19.838,26.438 20.893,26.438 21.525,27.069 21.525,27.536 21.985,27.997 22.015,27.997 22.078,28.059 v2(22.125,28.059)
VIOEXT: C43.2 R48.2 R49.2 R50.2 R51.2 R52.2 R54.2 R56.2 R58.2 R60.2 U5.14 U5.15 U8_S7.15 | length 20.1
  Top Layer w0.2: U8_S7.15@99.2,31.125 99.204,31.121 99.204,30.832 99.461,30.575 100.375,30.575 100.775,30.175 101.725,30.175 ; v2(101.688,30.572) 101.688,30.212 101.725,30.175 ; U5.14@103.21,31.125 103.21,30.55 ; U5.15@103.61,31.125 103.61,30.696 103.492,30.578 103.238,30.578 103.21,30.55 ; 101.725,30.175 v2(102.906,30.175) C43.2@102.927,30.197 102.927,30.267 103.21,30.55
  Top Layer w0.203: v2(104.095,29.627) R51.2@104.68,29.627 104.777,29.529 105.276,29.529 105.6,29.205 107.118,29.205 107.448,29.534 107.448,31.959 ; R52.2@107.048,30.476 107.443,30.476 ; R54.2@107.048,31.949 107.438,31.949 107.448,31.959 ; R56.2@107.048,33.422 107.437,33.422 ; R60.2@107.048,34.896 107.083,34.896 107.448,34.531 107.448,31.959
  Mid-Layer 1 w0.2: v2(101.688,30.572) v2(101.688,31.385) v2(101.688,32.198)
  Mid-Layer 1 w0.203: v2(102.906,30.175) 103.547,30.175 v2(104.095,29.627)
VSYS: C55.2 C56.2 C65.2 C66.2 C68.2 FB4.2 TP26.1 U9.4 | length 3.6
  Top Layer w0.125: 17.592,13.497 C66.2@17.727,13.497 ; 17.592,14.297 C65.2@17.727,14.297
  Top Layer w0.3: C55.2@16.827,13.297 17.027,13.497 17.592,13.497 ; C56.2@16.827,14.497 17.027,14.297 17.592,14.297
  Bottom Layer w0.125: TP26.1@8.44,16.51 8.513,16.583 v1(8.513,18.145)
  other v1: 16.3,13.9 16.825,13.9 15.773,13.927 8.513,18.645 8.513,19.145
XC1: U3.C31 X1.1 | length 5.3
  Top Layer w0.125: U3.C31@28.125,31.059 28.149,31.059 28.937,31.847 30.513,31.847 30.963,32.297 31.984,32.297 32.625,31.656 X1.1@32.625,31.588
XC2: U3.B30 X1.3 | length 4.6
  Top Layer w0.125: U3.B30@27.725,31.259 27.725,31.807 28.027,32.109 30.421,32.109 30.955,32.643 31.113,32.643 X1.3@31.36,32.891
pads on no net: D5. D5.4 Fid1.0 Fid2.0 Fid3.0 J4.0 J4.6 J4.7 J4.8 J4.9 J5. J5.C6 J6. J6.0 J6.A8 J6.B8 J8.10 M1.26 M1.31 M1.32 M1.33 M1.37 M1.81 M1.82 M1.83 M1.84 M1.85 M1.86 M1.87 M1.88 M1.89 M1.90 M1.91 M1.92 M1.93 M1.94 M1.95 M1.96 M1.97 M1.98 M1.100 M1.102 M1.103 M1.104 P18.7 P18.8 P19.7 P19.8 P19.9 P22.0 P22.3 P25.11 P25.13 P28.3 P28.7 P28.8 P28.9 P28.10 P29.0 P30.0 SW6.0 U1.4 U2. U3. U3.A1 U3.A21 U3.A31 U3.AG31 U3.AK2 U3.AK4 U3.AK6 U3.AL1 U3.AL31 U3.B10 U3.D2 U3.F2 U3.J1 U3.K2 U3.L31 U3.M2 U3.P2 U3.T2 U4.3 U4.7 U6.0 U6.4 U6.5 U8_S7.10 U8_S9.10 U9.7 U9.8 U9.9 U9.10 U9.11 U9.15 U9.18 U9.19 U9.23 U9.24 U9.25 U9.26 U9.27
copper on no net:
  other v1: 145.485,13.717 153.534,50.267

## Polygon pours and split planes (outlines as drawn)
NetC8_2 on Top Layer "VUSB" (solid, pour order 32): 8.9,29.6 10.4,29.6 cw(c10.4,29.4) 10.6,29.4 10.6,28.7 11.6,28.7 11.6,28.1 11,28.1 11,28.3 10,28.3 cw(c10,28.4) 9.9,28.4 9.9,28.9 ccw(c9.8,28.9) 9.8,29 9,29 cw(c9,29.1) 8.9,29.1
GND on Top Layer "Top_Layer-GND" (solid, remove dead copper, pour order 35): 0,0.001 0,63.501 142.284,63.501 142.284,0.001
VDD on Top Layer "NONET_L-01_P-001" (solid, pour order 29): 24.1,11.354 24.1,12.24 cw(c24.16,12.24) 24.16,12.3 25.1,12.3 25.1,11.3 24.154,11.3 cw(c24.154,11.354)
NetC8_2 on Top Layer "VUSB" (solid, pour order 31): 9.1,34.3 11.4,34.3 11.4,33.5 11.4,32.9 11.2,32.9 11.2,33.1 11.2,33.9 9.1,33.9
VDD_nRF on Top Layer "NONET_L-01_P-001" (solid, pour order 33): 114,23.953 115.271,23.953 115.9,23.953 115.9,22.121 cw(c115.609,22.121) 115.815,21.915 115.746,21.846 ccw(c116.082,21.509) 115.606,21.509 115.606,21.005 114.803,21.005 114.8,21.611 ccw(c114.629,21.611) 114.719,21.756 114.114,22.13 cw(c114.24,22.335) 114,22.335
GND on Bottom Layer "Bottom_Layer-GND" (solid, remove dead copper, pour order 18): 0,0.001 0,63.501 142.24,63.501 142.24,0.001
GND on Mid-Layer 2 "Mid_Layer_2-GND" (solid, remove dead copper, pour order 28): 0,0.001 0,63.501 155,63.501 155,0.001
GND on Mid-Layer 1 "Mid_Layer_1-GND" (solid, remove dead copper, pour order 22): 0,0.001 0,63.501 155,63.501 155,0.001

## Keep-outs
Top Layer:
  circle w0.152: c13.97,7.621 r2.4
  circle w0.152: c15.24,55.881 r2.4
  circle w0.152: c66.04,12.701 r2.4
  circle w0.152: c66.04,40.641 r2.4
  circle w0.152: c96.52,7.621 r2.4
  region: 109.775,55.15 110.225,55.15 110.225,54.375 109.775,54.375
  region: 103.75,55.15 104.2,55.15 104.2,54.525 103.75,54.525
  region: 139.325,36.725 143.625,36.725 143.625,34.6 139.325,34.6
  region: 115.475,28.05 116.45,28.05 116.45,27.55 115.475,27.55
  region: 116.675,27.55 117.45,27.55 117.45,26.925 116.675,26.925
  lines w0.152: 90.909,53.598 cw(c90.17,55.881) 91.891,54.208
Bottom Layer:
  circle w1.3: c127.127,11.177 r0.01
  circle w1.3: c39.37,16.803 r0.01
  circle w1.3: c22.987,13.965 r0.01
  circle w1.3: c9.869,7.113 r0.01
  circle w1.3: c22.987,13.965 r0.01
  circle w1.3: c34.163,26.544 r0.01
  circle w1.3: c125.476,2.065 r0.01
  circle w1.3: c83.82,14.733 r0.01
  circle w1.3: c86.97,16.15 r0.01
  circle w1.3: c88.804,18.912 r0.01
  circle w1.3: c82.839,19.442 r0.01
  circle w1.3: c53.721,22.079 r0.01
  circle w1.3: c111.379,54.484 r0.01
  circle w1.3: c114.808,48.979 r0.01
  circle w1.3: c113.284,46.61 r0.01
  circle w0.152: c13.97,7.621 r2.4
  circle w0.152: c15.24,55.881 r2.4
  circle w0.152: c66.04,12.701 r2.4
  circle w0.152: c96.52,7.621 r2.4
  lines w0.152: 67.712,42.363 ccw(c66.04,40.641) 68.297,41.458 ; 90.849,53.579 cw(c90.17,55.881) 91.929,54.248
Keep-Out Layer:
  circle w0.152: c79.1,0 r0.173
  circle w0.152: c78.3,0 r0.173
  circle w0.152: c77.5,0 r0.173
  circle w0.152: c76.7,0 r0.173
  circle w0.152: c75.9,0 r0.173
  circle w0.152: c79.1,63.5 r0.173
  circle w0.152: c78.3,63.5 r0.173
  circle w0.152: c77.5,63.5 r0.173
  circle w0.152: c76.7,63.5 r0.173
  circle w0.152: c75.9,63.5 r0.173
  circle w0.152: c141.6,63.5 r0.173
  circle w0.152: c140.8,63.5 r0.173
  circle w0.152: c140,63.5 r0.173
  circle w0.152: c139.2,63.5 r0.173
  circle w0.152: c138.4,63.5 r0.173
  circle w0.152: c141.6,0 r0.173
  circle w0.152: c140.8,0 r0.173
  circle w0.152: c140,0 r0.173
  circle w0.152: c139.2,0 r0.173
  circle w0.152: c138.4,0 r0.173
  circle w0.152: c16.6,0 r0.173
  circle w0.152: c15.8,0 r0.173
  circle w0.152: c15,0 r0.173
  circle w0.152: c14.2,0 r0.173
  circle w0.152: c13.4,0 r0.173
  circle w0.152: c16.6,63.5 r0.173
  circle w0.152: c15.8,63.5 r0.173
  circle w0.152: c15,63.5 r0.173
  circle w0.152: c14.2,63.5 r0.173
  circle w0.152: c13.4,63.5 r0.173
  circle w0.152: c155,51.9 r0.173
  circle w0.152: c155,52.7 r0.173
  circle w0.152: c155,53.5 r0.173
  circle w0.152: c155,54.3 r0.173
  circle w0.152: c155,55.1 r0.173
  circle w0.152: c155,8.4 r0.173
  circle w0.152: c155,9.2 r0.173
  circle w0.152: c155,10 r0.173
  circle w0.152: c155,10.8 r0.173
  circle w0.152: c155,11.6 r0.173
  circle w0.152: c0,8.4 r0.173
  circle w0.152: c0,9.2 r0.173
  circle w0.152: c0,10 r0.173
  circle w0.152: c0,10.8 r0.173
  circle w0.152: c0,11.6 r0.173
  circle w0.152: c0,51.9 r0.173
  circle w0.152: c0,52.7 r0.173
  circle w0.152: c0,53.5 r0.173
  circle w0.152: c0,54.3 r0.173
  circle w0.152: c0,55.1 r0.173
